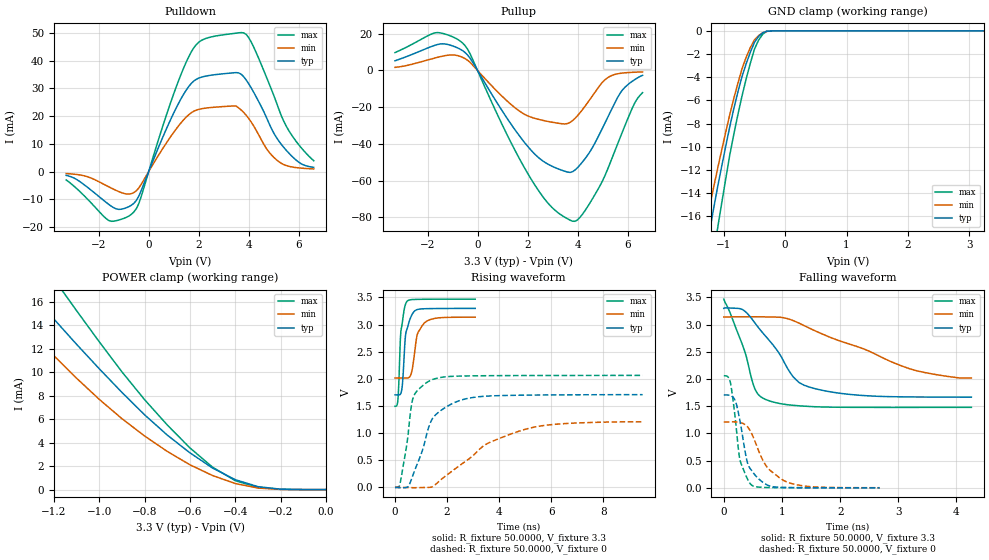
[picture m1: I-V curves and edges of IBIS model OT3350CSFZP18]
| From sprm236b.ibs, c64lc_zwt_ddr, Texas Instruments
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|   Model Cell OT3350CSFZP18
[Model]   OT3350CSFZP18
Model_type   3-state
Polarity   Non-Inverting
Enable   Active-Low
Cref =  15.0000pF
Rref =  100.0000M
Vref =  0V
Vmeas =  1.65
C_comp   1.576969p   1.539569p   1.618479p
[Temperature Range]   25   125   -40
[Voltage Range]   3.3   3.14   3.47
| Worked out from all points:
|   slope of the pulldown table from 0 to 0.495 V, typ, clamps not added: 45.1 ohm
|   slope of the pullup table from 0 to 0.495 V, typ, clamps not added: 43.8 ohm
|   GND clamp passes 1 mA (typ) near -0.50 V on its own axis
|   POWER clamp passes 1 mA (typ) near -0.42 V on its own axis
|   rising waveform, R_fixture 50.0000, V_fixture 3.3: 20-80 % time 194ps typ, 275ps min, 148ps max; typ from 1.71 V to 3.3 V
|   rising waveform, R_fixture 50.0000, V_fixture 0: 20-80 % time 848ps typ, 2.32ns min, 377ps max; typ from 0 V to 1.71 V
|   falling waveform, R_fixture 50.0000, V_fixture 3.3: 20-80 % time 662ps typ, 1.54ns min, 354ps max; typ from 3.3 V to 1.67 V
|   falling waveform, R_fixture 50.0000, V_fixture 0: 20-80 % time 208ps typ, 397ps min, 156ps max; typ from 1.71 V to 0.001 V
[POWER_clamp]
|   voltage   I(typ)   I(min)   I(max)
-3.3V     73.17mA    55.26mA    88.55mA
-1.467V   20.95mA    16.86mA    25.41mA
-1.433V   20.08mA    16.17mA    24.46mA
-1.3V     16.8mA     13.42mA    20.73mA
-1.267V   16.05mA    12.76mA    19.81mA
-1.167V   13.84mA    10.79mA    17.08mA
-1.133V   13.12mA    10.15mA    16.17mA
-800mV    6.379mA    4.573mA    7.671mA
-500mV    1.834mA    1.195mA    1.907mA
-400mV    842.5uA    517.3uA    755.2uA
-300mV    250.8uA    130.8uA    193.2uA
0V        16.51nA    109.4nA    12.33nA
[Pulldown]
|   voltage   I(typ)   I(min)   I(max)
-3.3V     -1.409mA   -742.3uA   -3.039mA
-1.6V     -11.86mA   -5.523mA   -17.67mA
-700mV    -12.23mA   -8.02mA    -15.5mA
-400mV    -8.953mA   -5.978mA   -11.65mA
900mV     19.24mA    12.9mA     25.53mA
1.7V      31.81mA    21.22mA    43.17mA
2.2V      34.3mA     22.8mA     47.78mA
3.7V      35.12mA    22.19mA    50.19mA
4.1V      30.16mA    17.85mA    46.75mA
5.1V      12.38mA    4.291mA    25.08mA
5.7V      5.751mA    1.686mA    13.37mA
6.6V      1.49mA     937.6uA    3.877mA
[Pullup]
|   voltage   I(typ)   I(min)   I(max)
-3.3V     5.276mA    1.679mA    9.74mA
-1.7V     13.73mA    6.8mA      20.49mA
-600mV    10.83mA    7.151mA    14.99mA
1.3V      -28.42mA   -18.04mA   -38.22mA
2.2V      -44.3mA    -25.71mA   -60.41mA
3V        -52.29mA   -28.23mA   -74.9mA
3.8V      -55.14mA   -27.31mA   -82.1mA
4.3V      -48.03mA   -19.44mA   -76.32mA
5.2V      -25.73mA   -3.973mA   -53.87mA
5.8V      -10.55mA   -1.41mA    -33.23mA
6.3V      -4.854mA   -937.9uA   -17.35mA
6.6V      -2.649mA   -791.8uA   -12.09mA
[GND_clamp]
|   voltage   I(typ)   I(min)   I(max)
-3.3V     -89.11mA   -68.37mA   -105.8mA
-1.3V     -19.47mA   -16.92mA   -23.74mA
-1.233V   -17.39mA   -15.23mA   -21.49mA
-1.167V   -15.39mA   -13.56mA   -19.26mA
-1.1V     -13.48mA   -11.9mA    -17.04mA
-1.033V   -11.69mA   -10.29mA   -14.87mA
-900mV    -8.232mA   -7.194mA   -10.67mA
-700mV    -3.904mA   -3.236mA   -5.567mA
-500mV    -996.2uA   -785.7uA   -1.587mA
-366.7mV  -172.3uA   -169.3uA   -300.2uA
-166.7mV  -4.076uA   -5.882uA   -4.359uA
3.233V    -14.06nA   2.34uA     -4.93nA
[Ramp]
| variable   typ   min   max
dV/dt_f  0.9853862/0.6594381n  0.7328027/1.720093n   1.201316/0.3554708n
dV/dt_r   1.031511/0.8517305n  0.7445348/2.434032n   1.243663/0.3755411n
R_load = 50
[Rising Waveform]
R_fixture = 50.0000
V_fixture = 3.3
V_fixture_min = 3.14
V_fixture_max = 3.47
|   time   V(typ)   V(min)   V(max)
0s        1.706V     2.016V     1.495V
112ps     1.706V     2.017V     1.62V
208ps     1.72V      2.017V     2.746V
256ps     1.79V      2.017V     2.96V
392ps     2.743V     2.016V     3.358V
448ps     2.9V       2.016V     3.42V
648ps     3.179V     2.143V     3.461V
856ps     3.277V     2.818V     3.465V
1.128ns   3.292V     3.031V     3.467V
3.08ns    3.299V     3.137V     3.47V
[Rising Waveform]
R_fixture = 50.0000
V_fixture = 0
V_fixture_min = 0
V_fixture_max = 0
|   time   V(typ)   V(min)   V(max)
0s        18.48uV    19.52uV    16.64uV
152ps     -2.171mV   27.07uV    10.62mV
216ps     -6.075mV   26.14uV    124.4mV
504ps     16.19mV    -1.33mV    977.3mV
680ps     216mV      -4.582mV   1.628V
1.376ns   1.213V     3.825mV    1.975V
2.568ns   1.614V     434.4mV    2.053V
3.52ns    1.682V     802.6mV    2.059V
4.776ns   1.699V     1.039V     2.061V
9.504ns   1.709V     1.209V     2.064V
[Falling Waveform]
R_fixture = 50.0000
V_fixture = 3.3
V_fixture_min = 3.14
V_fixture_max = 3.47
|   time   V(typ)   V(min)   V(max)
0s        3.3V       3.14V      3.47V
352ps     3.256V     3.145V     2.535V
536ps     3.031V     3.146V     1.815V
712ps     2.797V     3.143V     1.629V
920ps     2.523V     3.139V     1.56V
1.2ns     2.033V     3.072V     1.517V
1.48ns    1.85V      2.932V     1.496V
2.216ns   1.713V     2.625V     1.481V
3.248ns   1.672V     2.173V     1.48V
4.256ns   1.668V     2.02V      1.481V
[Falling Waveform]
R_fixture = 50.0000
V_fixture = 0
V_fixture_min = 0
V_fixture_max = 0
|   time   V(typ)   V(min)   V(max)
0s        1.707V     1.212V     2.062V
112ps     1.699V     1.213V     1.945V
208ps     1.569V     1.212V     1.169V
248ps     1.397V     1.207V     739.4mV
280ps     1.222V     1.201V     505mV
392ps     525.6mV    1.14V      198.6mV
480ps     317.6mV    996.7mV    49.3mV
728ps     63.63mV    405.8mV    7.758mV
1.104ns   6.74mV     99.48mV    2.989mV
2.68ns    1.306mV    3.198mV    410.3uV
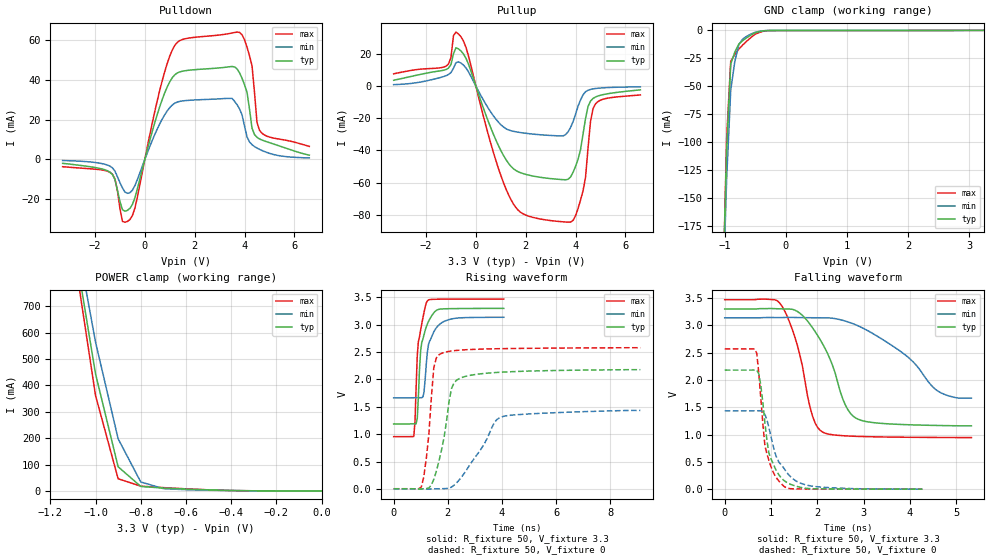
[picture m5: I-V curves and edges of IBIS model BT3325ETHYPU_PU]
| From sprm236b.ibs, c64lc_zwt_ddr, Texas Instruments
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[Model]   BT3325ETHYPU_PU
Model_type   I/O
Polarity   Non-Inverting
Enable   Active-Low
Vinl =  0.8V
Vinh =  2V
Cref =  15.0000pF
Rref =  100.0000M
Vref =  0V
Vmeas =  1.65
C_comp   2.566034p   2.494321p   2.623693p
[Model Spec]
Vinl   0.8V   0.8V   0.8V
Vinh   2V   2V   2V
[Temperature Range]   25   125   -40
[Voltage Range]   3.3   3.14   3.47
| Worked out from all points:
|   slope of the pulldown table from 0 to 0.495 V, typ, clamps not added: 22 ohm
|   slope of the pullup table from 0 to 0.495 V, typ, clamps not added: 22.7 ohm
|   GND clamp passes 1 mA (typ) near -0.42 V on its own axis
|   POWER clamp passes 1 mA (typ) near -0.34 V on its own axis
|   rising waveform, R_fixture 50, V_fixture 3.3: 20-80 % time 247ps typ, 302ps min, 216ps max; typ from 1.19 V to 3.3 V
|   rising waveform, R_fixture 50, V_fixture 0: 20-80 % time 465ps typ, 1.04ns min, 263ps max; typ from 0.002 V to 2.18 V
|   falling waveform, R_fixture 50, V_fixture 3.3: 20-80 % time 618ps typ, 1.19ns min, 417ps max; typ from 3.3 V to 1.16 V
|   falling waveform, R_fixture 50, V_fixture 0: 20-80 % time 260ps typ, 409ps min, 217ps max; typ from 2.18 V to 0.003 V
[POWER_clamp]
|   voltage   I(typ)   I(min)   I(max)
-3.3V     15.08A     13.67A     16.19A
-1.067V   791.8mA    876.7mA    739.7mA
-1.033V   617.9mA    720.5mA    550.8mA
-1V       444mA      564.3mA    361.9mA
-900mV    91.5mA     197.6mA    46.16mA
-800mV    17.11mA    33.99mA    18mA
-700mV    10.63mA    8.68mA     12.59mA
-400mV    1.748mA    1.071mA    1.568mA
-11.55fV  124.3nA    283.1nA    244.6nA
[Pulldown]
|   voltage   I(typ)   I(min)   I(max)
-3.3V     -2.009mA   -598.7uA   -3.704mA
-1.4V     -6.443mA   -3.405mA   -6.53mA
-900mV    -25.27mA   -14.31mA   -31.18mA
-600mV    -24.63mA   -16.76mA   -30.27mA
700mV     30.19mA    20.31mA    39.67mA
1.2V      42.48mA    28.23mA    57.23mA
3.7V      45.45mA    27.48mA    63.96mA
4.1V      33.69mA    11.27mA    56.39mA
4.3V      15.66mA    7.38mA     47.1mA
4.5V      11.07mA    5.671mA    18.53mA
4.6V      10.27mA    5.02mA     14.66mA
6.6V      2.127mA    698uA      6.501mA
[Pullup]
|   voltage   I(typ)   I(min)   I(max)
-3.3V     3.672mA    942uA      7.701mA
-1.2V     10.36mA    6.515mA    12.43mA
-900mV    20.11mA    11.14mA    31.42mA
-700mV    23.22mA    15.14mA    32.51mA
1.4V      -49.76mA   -27.7mA    -70.44mA
3.4V      -58.08mA   -30.96mA   -84.3mA
4.1V      -45.46mA   -12.4mA    -76.1mA
4.4V      -20.13mA   -3.457mA   -56.69mA
4.5V      -12.6mA    -2.531mA   -38.48mA
4.6V      -9.27mA    -2.014mA   -21.89mA
4.8V      -6.737mA   -1.451mA   -11.02mA
6.6V      -2.305mA   -414.2uA   -5.467mA
[GND_clamp]
|   voltage   I(typ)   I(min)   I(max)
-3.3V     -17.31A    -15.67A    -18.52A
-1.033V   -242.5mA   -247.9mA   -249.2mA
-966.7mV  -107.7mA   -133.3mA   -96.21mA
-900mV    -30.23mA   -53.64mA   -27.71mA
-833.3mV  -19.36mA   -27.93mA   -21.66mA
-766.7mV  -12.28mA   -12.57mA   -16.71mA
-700mV    -9.011mA   -7.551mA   -12.86mA
-566.7mV  -4.137mA   -3.208mA   -6.295mA
-500mV    -2.163mA   -1.683mA   -3.503mA
-433.3mV  -1.112mA   -895.4uA   -1.851mA
-300mV    -188.2uA   -143uA     -305.2uA
3.233V    -8.746uA   11.87uA    -45.21uA
[Ramp]
| variable   typ   min   max
dV/dt_f   1.301479/0.6270563n  0.9834451/1.27973n   1.527837/0.420318n
dV/dt_r   1.326222/0.4641024n  0.9119479/1.092418n   1.555289/0.2521662n
R_load = 50
[Rising Waveform]
R_fixture = 50
V_fixture = 3.3
V_fixture_min = 3.14
V_fixture_max = 3.47
|   time   V(typ)   V(min)   V(max)
0s        1.188V     1.665V     955.1mV
744ps     1.189V     1.666V     957.3mV
788ps     1.189V     1.667V     1.227V
872ps     1.284V     1.667V     2.426V
912ps     1.67V      1.667V     2.689V
996ps     2.518V     1.666V     2.903V
1.12ns    2.814V     1.765V     3.222V
1.244ns   3.011V     2.494V     3.437V
1.868ns   3.292V     3.063V     3.469V
4.068ns   3.299V     3.137V     3.47V
[Rising Waveform]
R_fixture = 50
V_fixture = 0
V_fixture_min = 0
V_fixture_max = 0
|   time   V(typ)   V(min)   V(max)
0s        1.984mV    1.288mV    2.678mV
1.02ns    -2.325mV   1.259mV    34.07mV
1.112ns   1.938mV    -1.251mV   217.1mV
1.3ns     16.85mV    -3.776mV   993.4mV
1.484ns   174.8mV    550.9uV    2.219V
1.672ns   505.4mV    2.433mV    2.451V
2.136ns   1.833V     31.86mV    2.52V
2.416ns   2.014V     159.4mV    2.535V
4ns       2.134V     1.318V     2.563V
9.116ns   2.179V     1.434V     2.58V
[Falling Waveform]
R_fixture = 50
V_fixture = 3.3
V_fixture_min = 3.14
V_fixture_max = 3.47
|   time   V(typ)   V(min)   V(max)
0s        3.3V       3.14V      3.47V
1.192ns   3.304V     3.143V     3.405V
1.572ns   3.253V     3.144V     2.623V
1.896ns   2.957V     3.141V     1.338V
2.112ns   2.663V     3.139V     1.048V
2.6ns     1.55V      3.08V      978.7mV
2.82ns    1.309V     3.013V     970.2mV
3.904ns   1.184V     2.455V     953.2mV
4.608ns   1.168V     1.794V     949mV
5.324ns   1.163V     1.669V     947.4mV
[Falling Waveform]
R_fixture = 50
V_fixture = 0
V_fixture_min = 0
V_fixture_max = 0
|   time   V(typ)   V(min)   V(max)
0s        2.182V     1.437V     2.57V
692ps     2.179V     1.437V     2.487V
780ps     1.901V     1.438V     1.662V
868ps     1.214V     1.37V      799.6mV
952ps     671.8mV    1.139V     536.4mV
996ps     561.4mV    974.2mV    420mV
1.128ns   320.6mV    564.4mV    195.7mV
1.3ns     147.8mV    357.4mV    41.49mV
1.912ns   10.57mV    55.52mV    4.523mV
4.264ns   2.889mV    4.438mV    2.657mV
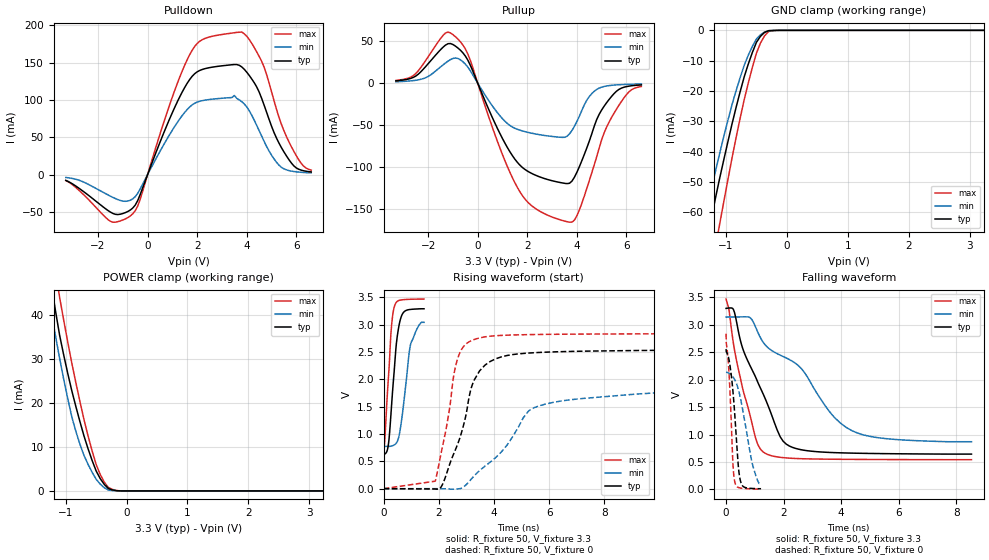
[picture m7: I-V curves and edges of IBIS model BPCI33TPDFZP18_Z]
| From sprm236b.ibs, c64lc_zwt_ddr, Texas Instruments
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[Model]   BPCI33TPDFZP18_Z
Model_type   I/O
Polarity   Non-Inverting
Enable   Active-Low
Vinl =  0.8
Vinh =  2.0
Cref =  10.0000pF
Rref =  50.0000
Vref =  1.5V
Vmeas =  1.5
C_comp   3.400798p   3.348868p   3.529696p
[Temperature Range]   25   125   -40
[Voltage Range]   3.3   3.14   3.47
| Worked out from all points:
|   slope of the pulldown table from 0 to 0.495 V, typ, clamps not added: 11.5 ohm
|   slope of the pullup table from 0 to 0.495 V, typ, clamps not added: 14.2 ohm
|   GND clamp passes 1 mA (typ) near -0.38 V on its own axis
|   POWER clamp passes 1 mA (typ) near -0.33 V on its own axis
|   rising waveform, R_fixture 50, V_fixture 3.3: 20-80 % time 251ps typ, 312ps min, 203ps max; typ from 0.619 V to 3.29 V
|   rising waveform, R_fixture 50, V_fixture 0: 20-80 % time 909ps typ, 3.22ns min, 573ps max; typ from 0 V to 2.55 V
|   falling waveform, R_fixture 50, V_fixture 3.3: 20-80 % time 1.24ns typ, 2.46ns min, 740ps max; typ from 3.3 V to 0.643 V
|   falling waveform, R_fixture 50, V_fixture 0: 20-80 % time 223ps typ, 423ps min, 146ps max; typ from 2.56 V to 0.012 V
[POWER_clamp]
|   voltage   I(typ)   I(min)   I(max)
-3.3V     266.8mA    206.4mA    325.6mA
-1.3V     53.18mA    45.61mA    63.86mA
-1.233V   46.77mA    40.36mA    56.56mA
-1.167V   40.86mA    35.21mA    49.96mA
-1.1V     35.42mA    30.15mA    44.05mA
-900mV    22.79mA    16.87mA    29.07mA
-700mV    12.51mA    8.084mA    16.24mA
-500mV    4.533mA    2.641mA    6.002mA
-366.7mV  1.47mA     728.9uA    2.002mA
-300mV    534.6uA    203uA      780.1uA
-100mV    3.163uA    1.609uA    6.87uA
3.233V    -6.376uA   -6.769uA   -6.673uA
[Pulldown]
|   voltage   I(typ)   I(min)   I(max)
-3.3V     -7.788mA   -3.889mA   -7.987mA
-1.5V     -50.3mA    -28.94mA   -62.59mA
-700mV    -47.57mA   -34.42mA   -55.53mA
-400mV    -34.9mA    -25.14mA   -42.3mA
900mV     75.57mA    54.22mA    94.66mA
1.8V      131.8mA    93.47mA    166.8mA
2.4V      142.6mA    100.2mA    183.5mA
3.8V      144.2mA    97.66mA    191mA
4.6V      102.2mA    51.63mA    151.8mA
5.3V      42.12mA    12.63mA    76.69mA
6.1V      7.063mA    3.322mA    19.68mA
6.6V      3.543mA    2.233mA    5.963mA
[Pullup]
|   voltage   I(typ)   I(min)   I(max)
-3.3V     2.84mA     1.735mA    3.327mA
-2.6V     6.94mA     3.146mA    9.053mA
-1.4V     43.04mA    21.89mA    57.16mA
-1V       46.23mA    29.6mA     58.04mA
-400mV    27.63mA    19.3mA     34.95mA
900mV     -60.4mA    -39.07mA   -77.82mA
1.7V      -97.84mA   -56.07mA   -129.6mA
3.7V      -119.6mA   -60.58mA   -166.1mA
4.1V      -99.72mA   -39.32mA   -151.4mA
5.2V      -23.22mA   -3.285mA   -52.37mA
6V        -4.027mA   -1.402mA   -13.57mA
6.6V      -2.032mA   -942.8uA   -3.85mA
[GND_clamp]
|   voltage   I(typ)   I(min)   I(max)
-3.3V     -301.2mA   -235.6mA   -364.4mA
-1.367V   -75.5mA    -63.63mA   -93.98mA
-1.3V     -68.14mA   -57.66mA   -85.98mA
-1.233V   -61.34mA   -51.8mA    -78.41mA
-1.1V     -48.49mA   -40.31mA   -63.55mA
-900mV    -30.85mA   -24.49mA   -42.05mA
-700mV    -15.32mA   -11.54mA   -22.85mA
-500mV    -3.958mA   -2.853mA   -7.561mA
-366.7mV  -691.7uA   -560.5uA   -1.825mA
-300mV    -116.7uA   -125.7uA   -398.3uA
-166.7mV  -12.04uA   -14.05uA   -28.61uA
3.233V    119.2nA    2.959uA    596nA
[Ramp]
| variable   typ   min   max
dV/dt_f   1.61237/1.248011n   1.412943/2.561355n   1.764449/0.7427376n
dV/dt_r   1.539406/0.9029799n   1.252676/3.794464n   1.706471/0.5745772n
R_load = 50
[Rising Waveform]
R_fixture = 50
V_fixture = 3.3
V_fixture_min = 3.14
V_fixture_max = 3.47
|   time   V(typ)   V(min)   V(max)
0s        618.6mV    772.4mV    535.8mV
8ps       626mV      772.5mV    685.6mV
176ps     822mV      772.4mV    2.057V
280ps     1.472V     778.3mV    2.943V
384ps     2.161V     799.4mV    3.323V
488ps     2.765V     855.6mV    3.423V
656ps     3.169V     1.27V      3.453V
976ps     3.278V     2.638V     3.464V
1.264ns   3.288V     2.974V     3.467V
1.464ns   3.29V      3.042V     3.468V
[Rising Waveform]
R_fixture = 50
V_fixture = 0
V_fixture_min = 0
V_fixture_max = 0
|   time   V(typ)   V(min)   V(max)
0s        23.63uV    16.46uV    33.77uV
1.872ns   -6.283mV   -641.3uV   136.9mV
2.112ns   55.11mV    -1.771mV   717.7mV
2.664ns   788.2mV    -5.543mV   2.346V
3.176ns   1.838V     172.8mV    2.706V
3.48ns    2.155V     331.9mV    2.758V
4.472ns   2.435V     793.7mV    2.807V
5.264ns   2.48V      1.425V     2.817V
6.656ns   2.508V     1.618V     2.825V
28.76ns   2.554V     2.04V      2.837V
[Falling Waveform]
R_fixture = 50
V_fixture = 3.3
V_fixture_min = 3.14
V_fixture_max = 3.47
|   time   V(typ)   V(min)   V(max)
0s        3.3V       3.14V      3.47V
96ps      3.307V     3.143V     3.298V
264ps     3.27V      3.143V     2.636V
600ps     2.538V     3.146V     1.79V
1.056ns   2.012V     2.923V     886.6mV
1.328ns   1.694V     2.656V     668.4mV
2.096ns   823.2mV    2.394V     572.9mV
2.616ns   721.8mV    2.202V     559.1mV
4.368ns   660.8mV    1.072V     546.7mV
8.528ns   642.7mV    868.5mV    540.8mV
[Falling Waveform]
R_fixture = 50
V_fixture = 0
V_fixture_min = 0
V_fixture_max = 0
|   time   V(typ)   V(min)   V(max)
0s        2.557V     2.136V     2.837V
8ps       2.509V     2.135V     2.67V
88ps      2.4V       2.122V     2.245V
160ps     2.171V     2.097V     1.501V
240ps     1.785V     2.05V      461.5mV
304ps     1.356V     1.997V     135.4mV
424ps     440mV      1.83V      35.17mV
520ps     118.8mV    1.61V      22.27mV
912ps     16.59mV    471.2mV    7.249mV
1.216ns   11.6mV     104.9mV    3.457mV
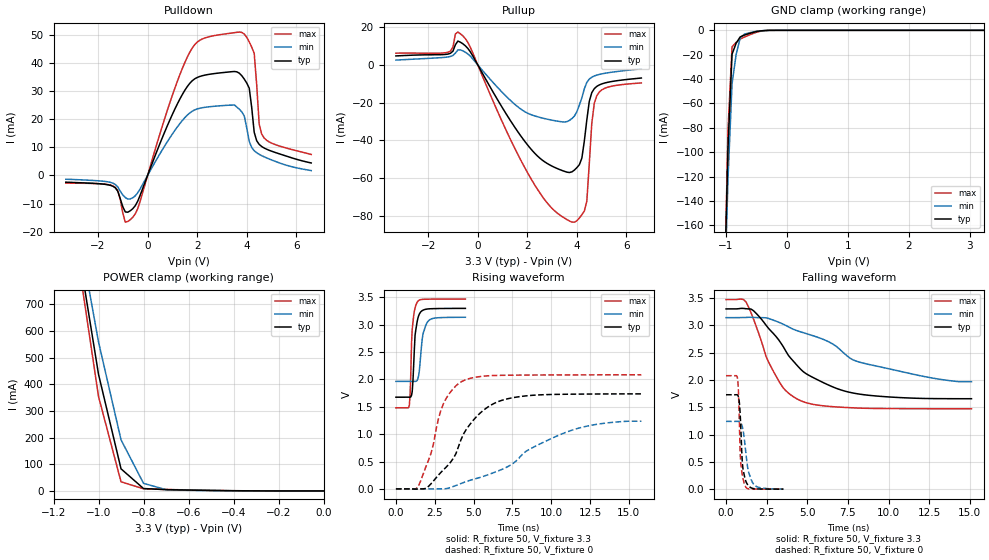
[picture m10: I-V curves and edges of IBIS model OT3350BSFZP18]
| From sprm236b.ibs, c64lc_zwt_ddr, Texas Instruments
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|   Model Cell OT3350BSFZP18
[Model]   OT3350BSFZP18
Model_type   3-state
Polarity   Non-Inverting
Enable   Active-Low
|Vinl =  0.8V
|Vinh =  2V
Cref =  15.0000pF
Rref =  100.0000M
Vref =  0V
Vmeas =  1.65
C_comp   1.61456p   1.57342p   1.650747p
[Model Spec]
|Vinl   0.8V   0.8V   0.8V
|Vinh   2V   2V   2V
[Temperature Range]   25   125   -40
[Voltage Range]   3.3   3.14   3.47
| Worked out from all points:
|   slope of the pulldown table from 0 to 0.495 V, typ, clamps not added: 44 ohm
|   slope of the pullup table from 0 to 0.495 V, typ, clamps not added: 42.8 ohm
|   GND clamp passes 1 mA (typ) near -0.50 V on its own axis
|   POWER clamp passes 1 mA (typ) near -0.41 V on its own axis
|   rising waveform, R_fixture 50, V_fixture 3.3: 20-80 % time 219ps typ, 303ps min, 177ps max; typ from 1.68 V to 3.3 V
|   rising waveform, R_fixture 50, V_fixture 0: 20-80 % time 2.38ns typ, 4.74ns min, 1.32ns max; typ from 0 V to 1.74 V
|   falling waveform, R_fixture 50, V_fixture 3.3: 20-80 % time 3.21ns typ, 5.71ns min, 1.74ns max; typ from 3.3 V to 1.66 V
|   falling waveform, R_fixture 50, V_fixture 0: 20-80 % time 194ps typ, 367ps min, 152ps max; typ from 1.73 V to 0.001 V
[POWER_clamp]
|   voltage   I(typ)   I(min)   I(max)
-3.3V     15.06A     13.65A     16.18A
-1.067V   785.4mA    870.9mA    732.6mA
-1.033V   611.4mA    714.8mA    543.3mA
-1V       437.3mA    558.7mA    354mA
-900mV    82.9mA     191.8mA    34.24mA
-800mV    9mA        28.45mA    7.998mA
-700mV    4.77mA     4.718mA    5.584mA
-400mV    849.6uA    521.8uA    759.5uA
-11.55fV  16.41nA    108.8nA    12.29nA
[Pulldown]
|   voltage   I(typ)   I(min)   I(max)
-3.3V     -2.42mA    -1.355mA   -2.742mA
-1.4V     -3.866mA   -2.765mA   -3.735mA
-900mV    -12.99mA   -7.877mA   -16.63mA
-700mV    -12.58mA   -8.352mA   -15.76mA
1.7V      32.7mA     22.18mA    43.75mA
3.6V      36.79mA    24.24mA    50.83mA
3.9V      34.2mA     21.09mA    50.21mA
4.1V      30.98mA    12.06mA    47.43mA
4.3V      15.29mA    8.758mA    43.35mA
4.5V      11.02mA    7.483mA    18.29mA
4.6V      10.26mA    7.017mA    14.72mA
6.6V      4.411mA    1.71mA     7.433mA
[Pullup]
|   voltage   I(typ)   I(min)   I(max)
-3.3V     4.711mA    2.514mA    6.162mA
-1.2V     5.694mA    4.172mA    6.672mA
-1V       7.233mA    4.973mA    9.382mA
-900mV    10.66mA    6.233mA    16.33mA
-600mV    11.14mA    7.39mA     15.31mA
2.2V      -45.34mA   -26.59mA   -61.37mA
3.8V      -56.6mA    -28.41mA   -83.18mA
4.2V      -49.35mA   -17.47mA   -79.29mA
4.4V      -29.21mA   -9.294mA   -72.14mA
4.6V      -14.75mA   -6.533mA   -31.02mA
4.8V      -11.42mA   -5.436mA   -16.39mA
6.6V      -6.969mA   -2.117mA   -9.572mA
[GND_clamp]
|   voltage   I(typ)   I(min)   I(max)
-3.3V     -17.3A     -15.65A    -18.51A
-1.033V   -231.4mA   -236.1mA   -236.2mA
-966.7mV  -96.45mA   -122.3mA   -82.03mA
-900mV    -19.63mA   -43.86mA   -13.55mA
-833.3mV  -10.63mA   -19.91mA   -9.887mA
-766.7mV  -5.403mA   -6.358mA   -7.243mA
-700mV    -3.961mA   -3.209mA   -5.618mA
-500mV    -1.004mA   -789.9uA   -1.595mA
-300mV    -29.29uA   -42.64uA   -45.65uA
3.233V    -14.17nA   2.341uA    -4.986nA
[Ramp]
| variable   typ   min   max
dV/dt_f  0.9942008/3.224722n   0.7652283/6.715832n   1.208762/1.738101n
dV/dt_r   1.047616/2.401502n   0.768072/4.954577n   1.255715/1.324692n
R_load = 50
[Rising Waveform]
R_fixture = 50
V_fixture = 3.3
V_fixture_min = 3.14
V_fixture_max = 3.47
|   time   V(typ)   V(min)   V(max)
0s        1.676V     1.965V     1.481V
864ps     1.676V     1.965V     1.528V
912ps     1.676V     1.965V     1.72V
1.048ns   1.777V     1.965V     2.918V
1.232ns   2.807V     1.965V     3.309V
1.368ns   3.059V     1.983V     3.411V
1.508ns   3.195V     2.161V     3.452V
1.736ns   3.265V     2.822V     3.465V
2.056ns   3.289V     3.059V     3.468V
4.472ns   3.299V     3.137V     3.47V
[Rising Waveform]
R_fixture = 50
V_fixture = 0
V_fixture_min = 0
V_fixture_max = 0
|   time   V(typ)   V(min)   V(max)
0s        17.64uV    18.18uV    16.31uV
1.448ns   -2.18mV    -981.8uV   48.09mV
2.256ns   92.16mV    -437.9uV   647.6mV
3.06ns    348.4mV    1.003mV    1.558V
3.708ns   564mV      45.65mV    1.838V
4.352ns   1.002V     116mV      1.979V
5.644ns   1.439V     230.4mV    2.06V
7.256ns   1.651V     414.7mV    2.078V
11.29ns   1.731V     1.069V     2.084V
15.8ns    1.737V     1.237V     2.085V
[Falling Waveform]
R_fixture = 50
V_fixture = 3.3
V_fixture_min = 3.14
V_fixture_max = 3.47
|   time   V(typ)   V(min)   V(max)
0s        3.3V       3.14V      3.47V
1.228ns   3.303V     3.143V     3.428V
1.692ns   3.266V     3.144V     3.113V
2.46ns    3.002V     3.137V     2.431V
3.076ns   2.795V     3.075V     2.07V
3.692ns   2.52V      2.995V     1.798V
4.616ns   2.188V     2.877V     1.617V
6.468ns   1.885V     2.674V     1.513V
8.008ns   1.75V      2.345V     1.487V
15.1ns    1.656V     1.968V     1.472V
[Falling Waveform]
R_fixture = 50
V_fixture = 0
V_fixture_min = 0
V_fixture_max = 0
|   time   V(typ)   V(min)   V(max)
0s        1.728V     1.24V      2.077V
716ps     1.722V     1.241V     2.016V
752ps     1.702V     1.242V     1.863V
824ps     1.573V     1.237V     1.164V
896ps     1.216V     1.218V     495.7mV
1.004ns   476.3mV    1.142V     253.1mV
1.184ns   176.4mV    757.2mV    54.73mV
1.364ns   69.09mV    342.2mV    7.509mV
1.728ns   8.978mV    80.32mV    1.636mV
3.528ns   862.7uV    3.171mV    128.2uV
